VERSION 5.8 ;
BUSBITCHARS "[]" ;
DIVIDERCHAR "/" ;
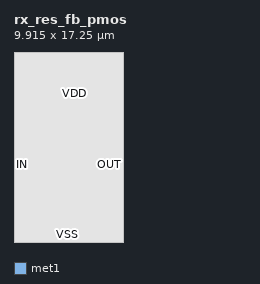
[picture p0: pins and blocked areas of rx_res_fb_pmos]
MACRO rx_res_fb_pmos
  CLASS BLOCK ;
  ORIGIN 0 0 ;
  FOREIGN rx_res_fb_pmos 0 0 ;
  SIZE 9.915 BY 17.250 ;
  SYMMETRY X Y ;
  PIN VDD
    DIRECTION INOUT ;
    USE POWER ;
    PORT
      LAYER met1 ;
        RECT 5.415 13.360 5.590 13.555 ;
    END
  END VDD
  PIN VSS
    DIRECTION INOUT ;
    USE GROUND ;
    PORT
      LAYER met1 ;
        RECT 4.755 0.620 4.930 0.815 ;
    END
  END VSS
  PIN IN
    DIRECTION INPUT ;
    USE SIGNAL ;
    PORT
      LAYER met1 ;
        RECT 0.645 6.945 0.830 7.135 ;
    END
  END IN
  PIN OUT
    DIRECTION OUTPUT ;
    USE SIGNAL ;
    PORT
      LAYER met1 ;
        RECT 9.055 6.975 9.245 7.115 ;
    END
  END OUT
  OBS
    LAYER met2 ;
      RECT 0.000 0.000 9.915 17.250 ;
    LAYER met3 ;
      RECT 0.000 0.000 9.915 17.250 ;
    LAYER met4 ;
      RECT 0.000 0.000 9.915 17.250 ;
    LAYER met5 ;
      RECT 0.000 0.000 9.915 17.250 ;
  END
END rx_res_fb_pmos
END LIBRARY
